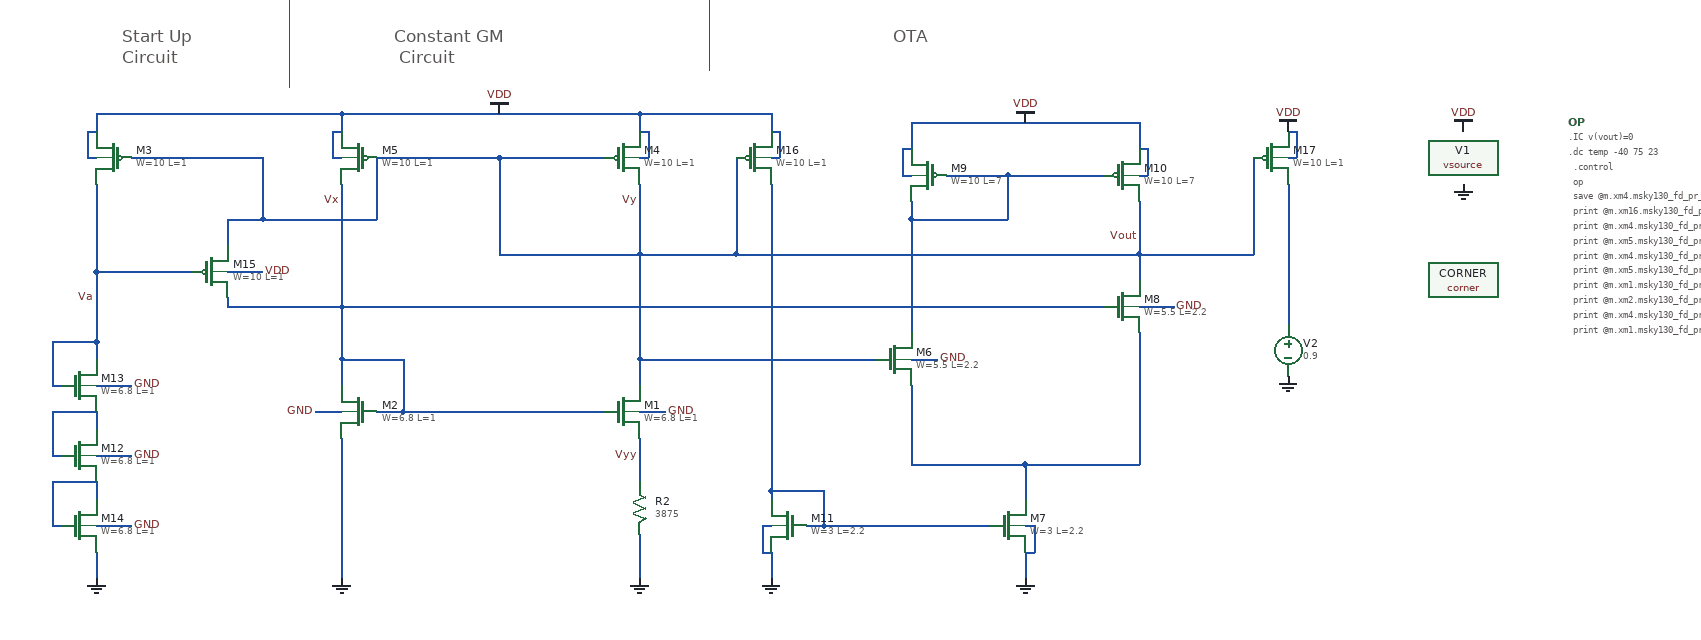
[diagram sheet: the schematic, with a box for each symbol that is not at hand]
v {xschem version=3.1.0 file_version=1.2 }
G {}
K {}
V {}
S {}
E {}
L 4 510 -110 510 10 {}
L 4 30 -110 30 30 {}
A 4 265 205 276.1340254296815 42.06432655357883 95.87134689284235 {}
A 4 755 205 276.1340254296815 42.06432655357883 95.87134689284235 {}
A 4 -100 105 160.0781059358212 51.34019174590991 77.31961650818019 {}
T {OTA} 720 -40 0 0 0.6 0.6 {}
T {Constant GM 
    Circuit} 150 -40 0 0 0.6 0.6 {}
T {Start Up 
Circuit} -160 -40 0 0 0.6 0.6 {}
N 130 110 270 110 {
lab=Vy}
N 90 60 90 80 {
lab=VDD}
N 90 60 430 60 {
lab=VDD}
N 430 60 430 80 {
lab=VDD}
N 90 140 90 280 {
lab=Vx}
N 160 400 390 400 {
lab=Vx}
N 80 110 90 110 {
lab=VDD}
N 80 80 80 110 {
lab=VDD}
N 80 80 90 80 {
lab=VDD}
N 430 110 440 110 {
lab=VDD}
N 440 80 440 110 {
lab=VDD}
N 430 80 440 80 {
lab=VDD}
N 430 400 460 400 {
lab=GND}
N 60 400 90 400 {
lab=GND}
N 430 430 430 480 {
lab=Vyy}
N 430 540 430 590 {
lab=GND}
N 430 140 430 220 {
lab=Vy}
N 430 220 430 340 {
lab=Vy}
N 90 430 90 590 {
lab=GND}
N 740 70 740 100 {
lab=VDD}
N 740 70 1000 70 {
lab=VDD}
N 1000 70 1000 100 {
lab=VDD}
N 740 340 770 340 {
lab=GND}
N 730 130 740 130 {
lab=VDD}
N 730 100 730 130 {
lab=VDD}
N 730 100 740 100 {
lab=VDD}
N 1000 130 1010 130 {
lab=VDD}
N 1010 100 1010 130 {
lab=VDD}
N 1000 100 1010 100 {
lab=VDD}
N 870 530 880 530 {
lab=GND}
N 880 530 880 560 {
lab=GND}
N 870 560 880 560 {
lab=GND}
N 870 560 870 590 {
lab=GND}
N 580 560 580 590 {
lab=GND}
N 570 530 580 530 {
lab=GND}
N 570 530 570 560 {
lab=GND}
N 570 560 580 560 {
lab=GND}
N 580 490 580 500 {
lab=#net1}
N 850 130 960 130 {
lab=#net2}
N 740 180 850 180 {
lab=#net2}
N 850 130 850 180 {
lab=#net2}
N 580 490 640 490 {
lab=#net1}
N 640 490 640 530 {
lab=#net1}
N 270 110 390 110 {
lab=Vy}
N 90 340 90 370 {
lab=Vx}
N 430 340 430 370 {
lab=Vy}
N 90 340 160 340 {
lab=Vx}
N 160 340 160 400 {
lab=Vx}
N 1000 280 1040 280 {
lab=GND}
N 1000 220 1000 250 {
lab=Vy}
N 740 370 740 460 {
lab=#net3}
N 870 460 1000 460 {
lab=#net3}
N 1000 310 1000 460 {
lab=#net3}
N 430 340 700 340 {
lab=Vy}
N 870 460 870 500 {
lab=#net3}
N 640 530 830 530 {
lab=#net1}
N 90 280 960 280 {
lab=Vx}
N 740 180 740 310 {
lab=#net2}
N 270 110 270 220 {
lab=Vy}
N 580 60 580 80 {
lab=VDD}
N 430 60 580 60 {
lab=VDD}
N 580 140 580 490 {
lab=#net1}
N -150 110 0 110 {
lab=Vy}
N 0 110 0 180 {
lab=Vy}
N 0 180 130 180 {
lab=Vy}
N 130 110 130 180 {
lab=Vy}
N -190 60 -190 80 {
lab=VDD}
N -190 60 90 60 {
lab=VDD}
N -200 110 -190 110 {
lab=VDD}
N -200 80 -200 110 {
lab=VDD}
N -200 80 -190 80 {
lab=VDD}
N -190 450 -150 450 {
lab=GND}
N -190 400 -190 420 {
lab=#net4}
N -240 400 -190 400 {
lab=#net4}
N -240 400 -240 450 {
lab=#net4}
N -240 450 -230 450 {
lab=#net4}
N -190 370 -150 370 {
lab=GND}
N -190 320 -190 340 {
lab=Va}
N -240 320 -190 320 {
lab=Va}
N -240 320 -240 370 {
lab=Va}
N -240 370 -230 370 {
lab=Va}
N -190 530 -150 530 {
lab=GND}
N -190 480 -190 500 {
lab=#net5}
N -240 480 -190 480 {
lab=#net5}
N -240 480 -240 530 {
lab=#net5}
N -240 530 -230 530 {
lab=#net5}
N -190 240 -190 320 {
lab=Va}
N -40 280 90 280 {
lab=Vx}
N -40 270 -40 280 {
lab=Vx}
N -40 180 -40 210 {
lab=Vy}
N -40 180 0 180 {
lab=Vy}
N -190 240 -80 240 {
lab=Va}
N -40 240 0 240 {
lab=VDD}
N 540 110 540 220 {
lab=Vy}
N 580 110 590 110 {
lab=VDD}
N 590 80 590 110 {
lab=VDD}
N 580 80 590 80 {
lab=VDD}
N 270 220 430 220 {
lab=Vy}
N 540 220 1000 220 {
lab=Vy}
N 1170 110 1180 110 {
lab=VDD}
N 1180 80 1180 110 {
lab=VDD}
N 1170 80 1180 80 {
lab=VDD}
N -190 560 -190 590 {
lab=GND}
N 1130 110 1130 220 {
lab=Vy}
N 1170 140 1170 300 {
lab=#net6}
N 740 160 740 180 {
lab=#net2}
N 780 130 850 130 {
lab=#net2}
N 620 530 640 530 {
lab=#net1}
N 90 280 90 340 {
lab=Vx}
N 130 400 160 400 {
lab=Vx}
N 740 460 870 460 {
lab=#net3}
N -190 140 -190 240 {
lab=Va}
N 430 220 540 220 {
lab=Vy}
N 1000 160 1000 220 {
lab=Vout}
N 1000 220 1130 220 {
lab=Vy}
C {sky130_fd_pr/nfet_01v8_lvt.sym} 410 400 0 0 {name=M1
L=1
W=6.8
nf=1
mult=4
ad="'int((nf+1)/2) * W/nf * 0.29'" 
pd="'2*int((nf+1)/2) * (W/nf + 0.29)'"
as="'int((nf+2)/2) * W/nf * 0.29'" 
ps="'2*int((nf+2)/2) * (W/nf + 0.29)'"
nrd="'0.29 / W'" nrs="'0.29 / W'"
sa=0 sb=0 sd=0
model=nfet_01v8_lvt
spiceprefix=X
}
C {sky130_fd_pr/nfet_01v8_lvt.sym} 110 400 0 1 {name=M2
L=1
W=6.8
nf=1
mult=1
ad="'int((nf+1)/2) * W/nf * 0.29'" 
pd="'2*int((nf+1)/2) * (W/nf + 0.29)'"
as="'int((nf+2)/2) * W/nf * 0.29'" 
ps="'2*int((nf+2)/2) * (W/nf + 0.29)'"
nrd="'0.29 / W'" nrs="'0.29 / W'"
sa=0 sb=0 sd=0
model=nfet_01v8_lvt
spiceprefix=X
}
C {sky130_fd_pr/pfet_01v8_lvt.sym} 410 110 0 0 {name=M4
L=1
W=10
nf=1
mult=10
ad="'int((nf+1)/2) * W/nf * 0.29'" 
pd="'2*int((nf+1)/2) * (W/nf + 0.29)'"
as="'int((nf+2)/2) * W/nf * 0.29'" 
ps="'2*int((nf+2)/2) * (W/nf + 0.29)'"
nrd="'0.29 / W'" nrs="'0.29 / W'"
sa=0 sb=0 sd=0
model=pfet_01v8_lvt
spiceprefix=X
}
C {sky130_fd_pr/pfet_01v8_lvt.sym} 110 110 0 1 {name=M5
L=1
W=10
nf=1
mult=10
ad="'int((nf+1)/2) * W/nf * 0.29'" 
pd="'2*int((nf+1)/2) * (W/nf + 0.29)'"
as="'int((nf+2)/2) * W/nf * 0.29'" 
ps="'2*int((nf+2)/2) * (W/nf + 0.29)'"
nrd="'0.29 / W'" nrs="'0.29 / W'"
sa=0 sb=0 sd=0
model=pfet_01v8_lvt
spiceprefix=X
}
C {devices/lab_pin.sym} 60 400 0 0 {name=l1 sig_type=std_logic lab=GND}
C {devices/lab_pin.sym} 460 400 0 1 {name=l2 sig_type=std_logic lab=GND}
C {devices/gnd.sym} 90 590 0 0 {name=l3 lab=GND}
C {devices/gnd.sym} 430 590 0 0 {name=l4 lab=GND}
C {devices/vdd.sym} 270 60 0 0 {name=l5 lab=VDD}
C {devices/res.sym} 430 510 0 0 {name=R2
value=3875
footprint=1206
device=resistor
m=1}
C {devices/lab_pin.sym} 430 160 0 0 {name=l9 sig_type=std_logic lab=Vy}
C {devices/lab_pin.sym} 90 160 0 0 {name=l10 sig_type=std_logic lab=Vx}
C {devices/lab_pin.sym} 430 450 0 0 {name=l12 sig_type=std_logic lab=Vyy}
C {devices/code_shown.sym} 1490 70 0 0 {name=OP only_toplevel=false value="
.IC v(vout)=0

.dc temp -40 75 23
 .control
    op
     save   @m.xm4.msky130_fd_pr__pfet_01v8_lvt[id]
     
     print  @m.xm16.msky130_fd_pr__pfet_01v8_lvt[id]
     print  @m.xm4.msky130_fd_pr__pfet_01v8_lvt[id]
     print  @m.xm5.msky130_fd_pr__pfet_01v8_lvt[id]
     
     print  @m.xm4.msky130_fd_pr__pfet_01v8_lvt[vds]
     print  @m.xm5.msky130_fd_pr__pfet_01v8_lvt[vds]
     print  @m.xm1.msky130_fd_pr__nfet_01v8_lvt[vds]
     print  @m.xm2.msky130_fd_pr__nfet_01v8_lvt[vds]

     print  @m.xm4.msky130_fd_pr__pfet_01v8_lvt[vgs]
     print  @m.xm1.msky130_fd_pr__nfet_01v8_lvt[vgs]
     print  @m.xm5.msky130_fd_pr__pfet_01v8_lvt[vgs]
     print  @m.xm2.msky130_fd_pr__nfet_01v8_lvt[vgs]

     print  @m.xm4.msky130_fd_pr__pfet_01v8_lvt[vth]
     print  @m.xm5.msky130_fd_pr__pfet_01v8_lvt[vth]
     print  @m.xm1.msky130_fd_pr__nfet_01v8_lvt[vth]
     print  @m.xm2.msky130_fd_pr__nfet_01v8_lvt[vth]
     print v(vx) v(vy) v(vyy)
dc v1 1.70 1.9 0.1m 
tran 0.1n 2u 
     plot  @m.xm4.msky130_fd_pr__pfet_01v8_lvt[id]
     plot  @m.xm16.msky130_fd_pr__pfet_01v8_lvt[id]
     plot i(v2)
  .endc 
.save all"
}
C {sky130_fd_pr/corner.sym} 1370 250 0 0 {name=CORNER only_toplevel=false corner=tt}
C {devices/vsource.sym} 1370 110 0 0 {name=V1 value=1.8}
C {devices/vdd.sym} 1370 80 0 0 {name=l6 lab=VDD}
C {devices/gnd.sym} 1370 140 0 0 {name=l7 lab=GND}
C {sky130_fd_pr/nfet_01v8_lvt.sym} 720 340 0 0 {name=M6
L=2.2
W=5.5
nf=1
mult=8
ad="'int((nf+1)/2) * W/nf * 0.29'" 
pd="'2*int((nf+1)/2) * (W/nf + 0.29)'"
as="'int((nf+2)/2) * W/nf * 0.29'" 
ps="'2*int((nf+2)/2) * (W/nf + 0.29)'"
nrd="'0.29 / W'" nrs="'0.29 / W'"
sa=0 sb=0 sd=0
model=nfet_01v8_lvt
spiceprefix=X
}
C {sky130_fd_pr/nfet_01v8_lvt.sym} 850 530 0 0 {name=M7
L=2.2
W=3
nf=1
mult=10
ad="'int((nf+1)/2) * W/nf * 0.29'" 
pd="'2*int((nf+1)/2) * (W/nf + 0.29)'"
as="'int((nf+2)/2) * W/nf * 0.29'" 
ps="'2*int((nf+2)/2) * (W/nf + 0.29)'"
nrd="'0.29 / W'" nrs="'0.29 / W'"
sa=0 sb=0 sd=0
model=nfet_01v8_lvt
spiceprefix=X
}
C {sky130_fd_pr/nfet_01v8_lvt.sym} 980 280 0 0 {name=M8
L=2.2
W=5.5
nf=1
mult=8
ad="'int((nf+1)/2) * W/nf * 0.29'" 
pd="'2*int((nf+1)/2) * (W/nf + 0.29)'"
as="'int((nf+2)/2) * W/nf * 0.29'" 
ps="'2*int((nf+2)/2) * (W/nf + 0.29)'"
nrd="'0.29 / W'" nrs="'0.29 / W'"
sa=0 sb=0 sd=0
model=nfet_01v8_lvt
spiceprefix=X
}
C {sky130_fd_pr/pfet_01v8_lvt.sym} 760 130 0 1 {name=M9
L=7
W=10
nf=1
mult=30
ad="'int((nf+1)/2) * W/nf * 0.29'" 
pd="'2*int((nf+1)/2) * (W/nf + 0.29)'"
as="'int((nf+2)/2) * W/nf * 0.29'" 
ps="'2*int((nf+2)/2) * (W/nf + 0.29)'"
nrd="'0.29 / W'" nrs="'0.29 / W'"
sa=0 sb=0 sd=0
model=pfet_01v8_lvt
spiceprefix=X
}
C {sky130_fd_pr/pfet_01v8_lvt.sym} 980 130 0 0 {name=M10
L=7
W=10
nf=1
mult=30
ad="'int((nf+1)/2) * W/nf * 0.29'" 
pd="'2*int((nf+1)/2) * (W/nf + 0.29)'"
as="'int((nf+2)/2) * W/nf * 0.29'" 
ps="'2*int((nf+2)/2) * (W/nf + 0.29)'"
nrd="'0.29 / W'" nrs="'0.29 / W'"
sa=0 sb=0 sd=0
model=pfet_01v8_lvt
spiceprefix=X
}
C {devices/lab_pin.sym} 1040 280 0 1 {name=l11 sig_type=std_logic lab=GND}
C {devices/lab_pin.sym} 770 340 0 1 {name=l13 sig_type=std_logic lab=GND}
C {sky130_fd_pr/nfet_01v8_lvt.sym} 600 530 0 1 {name=M11
L=2.2	
W=3
nf=1
mult=9
ad="'int((nf+1)/2) * W/nf * 0.29'" 
pd="'2*int((nf+1)/2) * (W/nf + 0.29)'"
as="'int((nf+2)/2) * W/nf * 0.29'" 
ps="'2*int((nf+2)/2) * (W/nf + 0.29)'"
nrd="'0.29 / W'" nrs="'0.29 / W'"
sa=0 sb=0 sd=0
model=nfet_01v8_lvt
spiceprefix=X
}
C {devices/gnd.sym} 580 590 0 0 {name=l15 lab=GND}
C {devices/vdd.sym} 870 70 0 0 {name=l8 lab=VDD}
C {devices/gnd.sym} 870 590 0 0 {name=l17 lab=GND}
C {devices/lab_pin.sym} 1000 200 0 0 {name=l14 sig_type=std_logic lab=Vout}
C {sky130_fd_pr/pfet_01v8_lvt.sym} -170 110 0 1 {name=M3
L=1
W=10
nf=1
mult=10
ad="'int((nf+1)/2) * W/nf * 0.29'" 
pd="'2*int((nf+1)/2) * (W/nf + 0.29)'"
as="'int((nf+2)/2) * W/nf * 0.29'" 
ps="'2*int((nf+2)/2) * (W/nf + 0.29)'"
nrd="'0.29 / W'" nrs="'0.29 / W'"
sa=0 sb=0 sd=0
model=pfet_01v8_lvt
spiceprefix=X
}
C {sky130_fd_pr/nfet_01v8_lvt.sym} -210 450 0 0 {name=M12
L=1
W=6.8
nf=1
mult=1
ad="'int((nf+1)/2) * W/nf * 0.29'" 
pd="'2*int((nf+1)/2) * (W/nf + 0.29)'"
as="'int((nf+2)/2) * W/nf * 0.29'" 
ps="'2*int((nf+2)/2) * (W/nf + 0.29)'"
nrd="'0.29 / W'" nrs="'0.29 / W'"
sa=0 sb=0 sd=0
model=nfet_01v8_lvt
spiceprefix=X
}
C {devices/lab_pin.sym} -150 450 0 1 {name=l16 sig_type=std_logic lab=GND}
C {sky130_fd_pr/nfet_01v8_lvt.sym} -210 370 0 0 {name=M13
L=1
W=6.8
nf=1
mult=1
ad="'int((nf+1)/2) * W/nf * 0.29'" 
pd="'2*int((nf+1)/2) * (W/nf + 0.29)'"
as="'int((nf+2)/2) * W/nf * 0.29'" 
ps="'2*int((nf+2)/2) * (W/nf + 0.29)'"
nrd="'0.29 / W'" nrs="'0.29 / W'"
sa=0 sb=0 sd=0
model=nfet_01v8_lvt
spiceprefix=X
}
C {devices/lab_pin.sym} -150 370 0 1 {name=l18 sig_type=std_logic lab=GND}
C {sky130_fd_pr/nfet_01v8_lvt.sym} -210 530 0 0 {name=M14
L=1
W=6.8
nf=1
mult=1
ad="'int((nf+1)/2) * W/nf * 0.29'" 
pd="'2*int((nf+1)/2) * (W/nf + 0.29)'"
as="'int((nf+2)/2) * W/nf * 0.29'" 
ps="'2*int((nf+2)/2) * (W/nf + 0.29)'"
nrd="'0.29 / W'" nrs="'0.29 / W'"
sa=0 sb=0 sd=0
model=nfet_01v8_lvt
spiceprefix=X
}
C {devices/lab_pin.sym} -150 530 0 1 {name=l19 sig_type=std_logic lab=GND}
C {devices/gnd.sym} -190 590 0 0 {name=l20 lab=GND}
C {sky130_fd_pr/pfet_01v8_lvt.sym} -60 240 0 0 {name=M15
L=1
W=10
nf=1
mult=40
ad="'int((nf+1)/2) * W/nf * 0.29'" 
pd="'2*int((nf+1)/2) * (W/nf + 0.29)'"
as="'int((nf+2)/2) * W/nf * 0.29'" 
ps="'2*int((nf+2)/2) * (W/nf + 0.29)'"
nrd="'0.29 / W'" nrs="'0.29 / W'"
sa=0 sb=0 sd=0
model=pfet_01v8_lvt
spiceprefix=X
}
C {devices/lab_pin.sym} 0 240 0 1 {name=l21 sig_type=std_logic lab=VDD}
C {devices/lab_pin.sym} -190 270 0 0 {name=l22 sig_type=std_logic lab=Va}
C {sky130_fd_pr/pfet_01v8_lvt.sym} 560 110 0 0 {name=M16
L=1
W=10
nf=1
mult=20
ad="'int((nf+1)/2) * W/nf * 0.29'" 
pd="'2*int((nf+1)/2) * (W/nf + 0.29)'"
as="'int((nf+2)/2) * W/nf * 0.29'" 
ps="'2*int((nf+2)/2) * (W/nf + 0.29)'"
nrd="'0.29 / W'" nrs="'0.29 / W'"
sa=0 sb=0 sd=0
model=pfet_01v8_lvt
spiceprefix=X
}
C {sky130_fd_pr/pfet_01v8_lvt.sym} 1150 110 0 0 {name=M17
L=1
W=10
nf=1
mult=20
ad="'int((nf+1)/2) * W/nf * 0.29'" 
pd="'2*int((nf+1)/2) * (W/nf + 0.29)'"
as="'int((nf+2)/2) * W/nf * 0.29'" 
ps="'2*int((nf+2)/2) * (W/nf + 0.29)'"
nrd="'0.29 / W'" nrs="'0.29 / W'"
sa=0 sb=0 sd=0
model=pfet_01v8_lvt
spiceprefix=X
}
C {devices/vdd.sym} 1170 80 0 0 {name=l23 lab=VDD}
C {devices/vsource.sym} 1170 330 0 0 {name=V2 value=0.9}
C {devices/gnd.sym} 1170 360 0 0 {name=l24 lab=GND}
